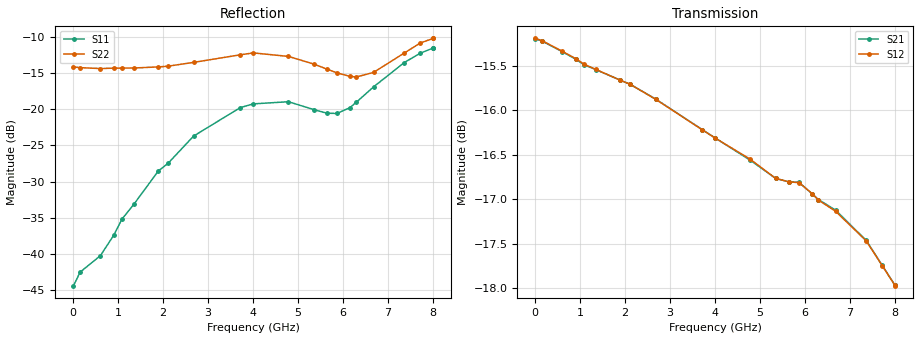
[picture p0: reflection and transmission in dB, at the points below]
! DEVICE ID: PE43712
! File Path: z:\PE43713\PE43713_CHAR_NOM_04292014\AMB\3p300\LS_ATT_14p00dB\PE43713_AMB_3p300V_3p000V_0p000V_LS_ATT_14p00dB_S2P_SN_10_A0139A.s2p
! Serial: 10
! Lot: A0139A
! Temp: 25C
! VDD: 3.300
! VSS: 0.000
! Control_Hi: 3.000
! Control_Lo: 0.000
! Attenuation Step: 14.00dB
! Port 1: RF1
! Port 2: RF2
! ThroughPath:1-2
! IDD: 0.0001472955
! ISS: -1.295e-007
#  Hz  S  RI  R  50
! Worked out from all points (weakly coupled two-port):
!   801 points, 10 MHz to 8.01 GHz, reference 50 ohm
!   highest |S21| = -15.20 dB at 10 MHz (marker M1); lowest = -18.0 dB at 8 GHz (marker M2)
!   lowest |S11| = -44.4 dB at 10 MHz (marker M3), VSWR 1.01, Z = 50.6 + j0.0438 ohm
!   |S11| at or under -10 dB: start of sweep to end of sweep
!   |S22| runs from -15.5 to -10.2 dB; largest |S21 - S12| = 0.00063
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1e7  0.00599 0.000432  0.1738 -0.000926  0.1739 -0.000888  -0.1963 0.00132
1.6e8  0.0071 0.00229  0.1729 -0.0114  0.173 -0.0114  -0.194 0.0127
6.1e8  0.00656 0.00714  0.166 -0.0407  0.1661 -0.0407  -0.1868 0.0422
9.1e8  0.00554 0.0123  0.1589 -0.0583  0.159 -0.0584  -0.1826 0.0621
1.09e9  0.00549 0.0165  0.1537 -0.068  0.1538 -0.0681  -0.1779 0.0748
1.35e9  0.00634 0.021  0.1459 -0.0813  0.1459 -0.0814  -0.1708 0.0904
1.9e9  0.0118 0.0356  0.1256 -0.1066  0.1256 -0.1066  -0.1496 0.1276
2.11e9  0.0142 0.0397  0.1167 -0.1151  0.1167 -0.1151  -0.1419 0.1393
2.68e9  0.0256 0.06  0.0895 -0.1336  0.0894 -0.1336  -0.1103 0.1803
3.72e9  0.032 0.0977  0.0343 -0.1507  0.0341 -0.1507  -0.0726 0.2272
4.01e9  0.0319 0.1043  0.0189 -0.1517  0.0188 -0.1517  -0.0678 0.2363
4.79e9  0.0321 0.1082  -0.0206 -0.1471  -0.0206 -0.1473  -0.0437 0.2283
5.35e9  0.0431 0.0898  -0.0461 -0.1376  -0.0461 -0.1376  -0.0199 0.2049
5.64e9  0.0534 0.0774  -0.0583 -0.1322  -0.0583 -0.1322  0.0039 0.19
5.87e9  0.0633 0.0689  -0.0692 -0.1267  -0.0691 -0.1267  0.0266 0.1768
6.16e9  0.0813 0.0631  -0.0815 -0.1166  -0.0813 -0.1168  0.0605 0.1578
6.3e9  0.094 0.0611  -0.086 -0.112  -0.0857 -0.1121  0.0791 0.1477
6.68e9  0.1297 0.06  -0.0985 -0.0985  -0.0982 -0.0985  0.1287 0.126
7.36e9  0.1984 0.0702  -0.1155 -0.0679  -0.1154 -0.0679  0.2141 0.119
7.72e9  0.2317 0.0791  -0.1188 -0.052  -0.1187 -0.0521  0.2599 0.1238
8e9  0.2498 0.0891  -0.1198 -0.0404  -0.1197 -0.0406  0.2828 0.1254
8.01e9  0.2504 0.0899  -0.1198 -0.0402  -0.1197 -0.0404  0.2835 0.1254
